VERSION 5.7 ;
  NOWIREEXTENSIONATPIN ON ;
  DIVIDERCHAR "/" ;
  BUSBITCHARS "[]" ;
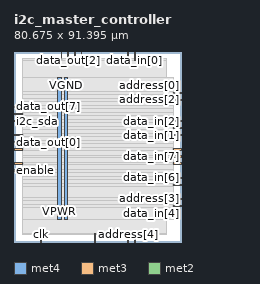
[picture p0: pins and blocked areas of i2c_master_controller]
MACRO i2c_master_controller
  CLASS BLOCK ;
  FOREIGN i2c_master_controller ;
  ORIGIN 0.000 0.000 ;
  SIZE 80.675 BY 91.395 ;
  PIN VGND
    DIRECTION INOUT ;
    USE GROUND ;
    PORT
      LAYER met4 ;
        RECT 24.340 10.640 25.940 79.120 ;
    END
  END VGND
  PIN VPWR
    DIRECTION INOUT ;
    USE POWER ;
    PORT
      LAYER met4 ;
        RECT 21.040 10.640 22.640 79.120 ;
    END
  END VPWR
  PIN address[0]
    DIRECTION INPUT ;
    USE SIGNAL ;
    ANTENNAGATEAREA 0.196500 ;
    PORT
      LAYER met3 ;
        RECT 76.675 71.440 80.675 72.040 ;
    END
  END address[0]
  PIN address[1]
    DIRECTION INPUT ;
    USE SIGNAL ;
    ANTENNAGATEAREA 0.196500 ;
    PORT
      LAYER met2 ;
        RECT 54.830 87.395 55.110 91.395 ;
    END
  END address[1]
  PIN address[2]
    DIRECTION INPUT ;
    USE SIGNAL ;
    ANTENNAGATEAREA 0.196500 ;
    PORT
      LAYER met3 ;
        RECT 76.675 68.040 80.675 68.640 ;
    END
  END address[2]
  PIN address[3]
    DIRECTION INPUT ;
    USE SIGNAL ;
    ANTENNAGATEAREA 0.196500 ;
    PORT
      LAYER met3 ;
        RECT 76.675 20.440 80.675 21.040 ;
    END
  END address[3]
  PIN address[4]
    DIRECTION INPUT ;
    USE SIGNAL ;
    ANTENNAGATEAREA 0.196500 ;
    PORT
      LAYER met2 ;
        RECT 54.830 0.000 55.110 4.000 ;
    END
  END address[4]
  PIN address[5]
    DIRECTION INPUT ;
    USE SIGNAL ;
    ANTENNAGATEAREA 0.196500 ;
    PORT
      LAYER met3 ;
        RECT 76.675 27.240 80.675 27.840 ;
    END
  END address[5]
  PIN address[6]
    DIRECTION INPUT ;
    USE SIGNAL ;
    ANTENNAGATEAREA 0.196500 ;
    PORT
      LAYER met3 ;
        RECT 76.675 37.440 80.675 38.040 ;
    END
  END address[6]
  PIN clk
    DIRECTION INPUT ;
    USE SIGNAL ;
    ANTENNAGATEAREA 0.852000 ;
    PORT
      LAYER met2 ;
        RECT 12.970 0.000 13.250 4.000 ;
    END
  END clk
  PIN data_in[0]
    DIRECTION INPUT ;
    USE SIGNAL ;
    ANTENNAGATEAREA 0.196500 ;
    PORT
      LAYER met2 ;
        RECT 58.050 87.395 58.330 91.395 ;
    END
  END data_in[0]
  PIN data_in[1]
    DIRECTION INPUT ;
    USE SIGNAL ;
    ANTENNAGATEAREA 0.196500 ;
    PORT
      LAYER met3 ;
        RECT 76.675 54.440 80.675 55.040 ;
    END
  END data_in[1]
  PIN data_in[2]
    DIRECTION INPUT ;
    USE SIGNAL ;
    ANTENNAGATEAREA 0.196500 ;
    PORT
      LAYER met3 ;
        RECT 76.675 57.840 80.675 58.440 ;
    END
  END data_in[2]
  PIN data_in[3]
    DIRECTION INPUT ;
    USE SIGNAL ;
    ANTENNAGATEAREA 0.196500 ;
    PORT
      LAYER met3 ;
        RECT 76.675 51.040 80.675 51.640 ;
    END
  END data_in[3]
  PIN data_in[4]
    DIRECTION INPUT ;
    USE SIGNAL ;
    ANTENNAGATEAREA 0.196500 ;
    PORT
      LAYER met3 ;
        RECT 76.675 17.040 80.675 17.640 ;
    END
  END data_in[4]
  PIN data_in[5]
    DIRECTION INPUT ;
    USE SIGNAL ;
    ANTENNAGATEAREA 0.196500 ;
    PORT
      LAYER met2 ;
        RECT 58.050 0.000 58.330 4.000 ;
    END
  END data_in[5]
  PIN data_in[6]
    DIRECTION INPUT ;
    USE SIGNAL ;
    ANTENNAGATEAREA 0.196500 ;
    PORT
      LAYER met3 ;
        RECT 76.675 30.640 80.675 31.240 ;
    END
  END data_in[6]
  PIN data_in[7]
    DIRECTION INPUT ;
    USE SIGNAL ;
    ANTENNAGATEAREA 0.196500 ;
    PORT
      LAYER met3 ;
        RECT 76.675 40.840 80.675 41.440 ;
    END
  END data_in[7]
  PIN data_out[0]
    DIRECTION OUTPUT ;
    USE SIGNAL ;
    ANTENNADIFFAREA 0.445500 ;
    PORT
      LAYER met3 ;
        RECT 0.000 47.640 4.000 48.240 ;
    END
  END data_out[0]
  PIN data_out[1]
    DIRECTION OUTPUT ;
    USE SIGNAL ;
    ANTENNADIFFAREA 0.445500 ;
    PORT
      LAYER met3 ;
        RECT 0.000 51.040 4.000 51.640 ;
    END
  END data_out[1]
  PIN data_out[2]
    DIRECTION OUTPUT ;
    USE SIGNAL ;
    ANTENNADIFFAREA 0.445500 ;
    PORT
      LAYER met2 ;
        RECT 25.850 87.395 26.130 91.395 ;
    END
  END data_out[2]
  PIN data_out[3]
    DIRECTION OUTPUT ;
    USE SIGNAL ;
    ANTENNADIFFAREA 0.445500 ;
    PORT
      LAYER met2 ;
        RECT 32.290 87.395 32.570 91.395 ;
    END
  END data_out[3]
  PIN data_out[4]
    DIRECTION OUTPUT ;
    USE SIGNAL ;
    ANTENNADIFFAREA 0.445500 ;
    PORT
      LAYER met3 ;
        RECT 0.000 61.240 4.000 61.840 ;
    END
  END data_out[4]
  PIN data_out[5]
    DIRECTION OUTPUT ;
    USE SIGNAL ;
    ANTENNADIFFAREA 0.445500 ;
    PORT
      LAYER met2 ;
        RECT 22.630 87.395 22.910 91.395 ;
    END
  END data_out[5]
  PIN data_out[6]
    DIRECTION OUTPUT ;
    USE SIGNAL ;
    ANTENNADIFFAREA 0.445500 ;
    PORT
      LAYER met2 ;
        RECT 29.070 87.395 29.350 91.395 ;
    END
  END data_out[6]
  PIN data_out[7]
    DIRECTION OUTPUT ;
    USE SIGNAL ;
    ANTENNADIFFAREA 0.445500 ;
    PORT
      LAYER met3 ;
        RECT 0.000 64.640 4.000 65.240 ;
    END
  END data_out[7]
  PIN enable
    DIRECTION INPUT ;
    USE SIGNAL ;
    ANTENNAGATEAREA 0.196500 ;
    PORT
      LAYER met3 ;
        RECT 0.000 34.040 4.000 34.640 ;
    END
  END enable
  PIN i2c_scl
    DIRECTION INOUT ;
    USE SIGNAL ;
    ANTENNADIFFAREA 1.431000 ;
    PORT
      LAYER met2 ;
        RECT 38.730 0.000 39.010 4.000 ;
    END
  END i2c_scl
  PIN i2c_sda
    DIRECTION INOUT ;
    USE SIGNAL ;
    ANTENNAGATEAREA 1.615500 ;
    ANTENNADIFFAREA 1.782000 ;
    PORT
      LAYER met3 ;
        RECT 0.000 57.840 4.000 58.440 ;
    END
  END i2c_sda
  PIN ready
    DIRECTION OUTPUT ;
    USE SIGNAL ;
    ANTENNADIFFAREA 0.445500 ;
    PORT
      LAYER met3 ;
        RECT 0.000 37.440 4.000 38.040 ;
    END
  END ready
  PIN rst
    DIRECTION INPUT ;
    USE SIGNAL ;
    ANTENNAGATEAREA 0.196500 ;
    PORT
      LAYER met3 ;
        RECT 0.000 44.240 4.000 44.840 ;
    END
  END rst
  PIN rw
    DIRECTION INPUT ;
    USE SIGNAL ;
    ANTENNAGATEAREA 0.196500 ;
    PORT
      LAYER met3 ;
        RECT 76.675 44.240 80.675 44.840 ;
    END
  END rw
  OBS
      LAYER nwell ;
        RECT 5.330 10.795 75.170 79.070 ;
      LAYER li1 ;
        RECT 5.520 10.795 74.980 78.965 ;
      LAYER met1 ;
        RECT 4.210 10.640 74.980 79.120 ;
      LAYER met2 ;
        RECT 4.230 87.115 22.350 88.130 ;
        RECT 23.190 87.115 25.570 88.130 ;
        RECT 26.410 87.115 28.790 88.130 ;
        RECT 29.630 87.115 32.010 88.130 ;
        RECT 32.850 87.115 54.550 88.130 ;
        RECT 55.390 87.115 57.770 88.130 ;
        RECT 58.610 87.115 73.510 88.130 ;
        RECT 4.230 4.280 73.510 87.115 ;
        RECT 4.230 3.670 12.690 4.280 ;
        RECT 13.530 3.670 38.450 4.280 ;
        RECT 39.290 3.670 54.550 4.280 ;
        RECT 55.390 3.670 57.770 4.280 ;
        RECT 58.610 3.670 73.510 4.280 ;
      LAYER met3 ;
        RECT 3.990 72.440 76.675 79.045 ;
        RECT 3.990 71.040 76.275 72.440 ;
        RECT 3.990 69.040 76.675 71.040 ;
        RECT 3.990 67.640 76.275 69.040 ;
        RECT 3.990 65.640 76.675 67.640 ;
        RECT 4.400 64.240 76.675 65.640 ;
        RECT 3.990 62.240 76.675 64.240 ;
        RECT 4.400 60.840 76.675 62.240 ;
        RECT 3.990 58.840 76.675 60.840 ;
        RECT 4.400 57.440 76.275 58.840 ;
        RECT 3.990 55.440 76.675 57.440 ;
        RECT 3.990 54.040 76.275 55.440 ;
        RECT 3.990 52.040 76.675 54.040 ;
        RECT 4.400 50.640 76.275 52.040 ;
        RECT 3.990 48.640 76.675 50.640 ;
        RECT 4.400 47.240 76.675 48.640 ;
        RECT 3.990 45.240 76.675 47.240 ;
        RECT 4.400 43.840 76.275 45.240 ;
        RECT 3.990 41.840 76.675 43.840 ;
        RECT 3.990 40.440 76.275 41.840 ;
        RECT 3.990 38.440 76.675 40.440 ;
        RECT 4.400 37.040 76.275 38.440 ;
        RECT 3.990 35.040 76.675 37.040 ;
        RECT 4.400 33.640 76.675 35.040 ;
        RECT 3.990 31.640 76.675 33.640 ;
        RECT 3.990 30.240 76.275 31.640 ;
        RECT 3.990 28.240 76.675 30.240 ;
        RECT 3.990 26.840 76.275 28.240 ;
        RECT 3.990 21.440 76.675 26.840 ;
        RECT 3.990 20.040 76.275 21.440 ;
        RECT 3.990 18.040 76.675 20.040 ;
        RECT 3.990 16.640 76.275 18.040 ;
        RECT 3.990 10.715 76.675 16.640 ;
  END
END i2c_master_controller
END LIBRARY

